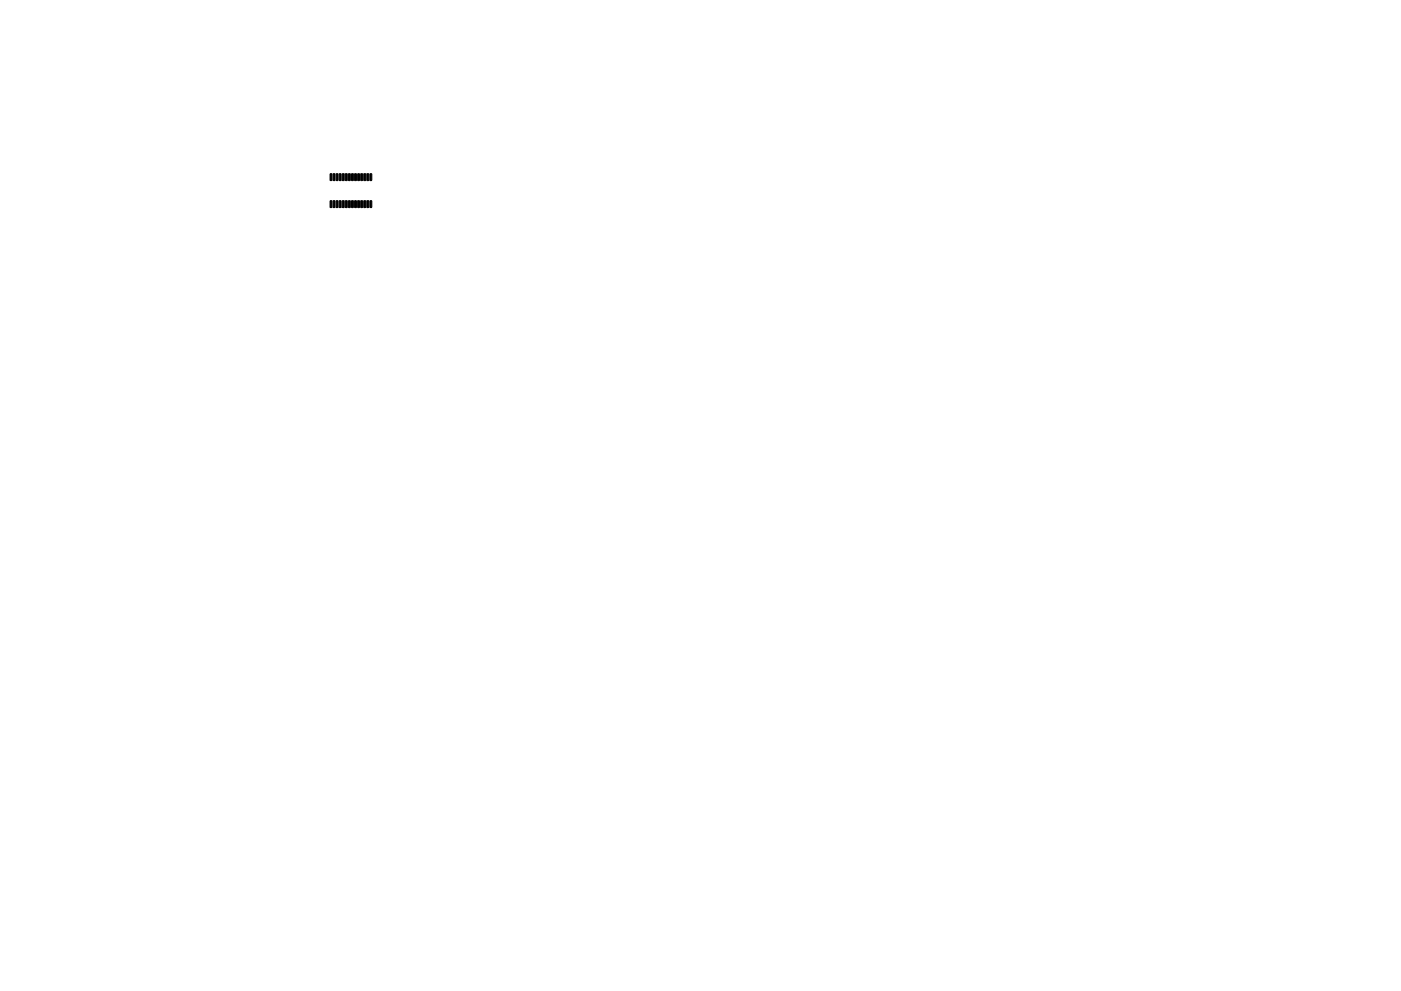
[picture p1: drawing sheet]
<svg xmlns="http://www.w3.org/2000/svg" width="297mm" height="210mm" viewBox="0 0 297 210" stroke-linecap="round" stroke-linejoin="round" font-family="sans-serif">
<g fill="#000" stroke="#000" stroke-width=".21">
<path d="M70 36.9h.4l-.1 1.4-.3-.1zM70.7 36.9h.3l-.1 1.4-.3-.1zM71.3 36.9h.4l-.1 1.4-.3-.1zM72 36.9h.3l-.1 1.4-.3-.1zM72.6 36.9h.4l-.1 1.4-.3-.1zM73.3 36.9h.3l-.1 1.4-.3-.1zM73.9 36.9h.4l-.1 1.4-.3-.1zM74.6 36.9h.3l-.1 1.4-.3-.1zM75.2 36.9h.4l-.1 1.4-.3-.1zM75.9 36.9h.3l-.1 1.4-.3-.1zM76.5 36.9h.4l-.1 1.4-.3-.1zM77.2 36.9h.3l-.1 1.4-.3-.1z"/>
<path d="M77.8 36.9h.4l-.1 1.4-.3-.1zM78.5 36.9h.3l-.1 1.4-.3-.1zM70 42.6l.4 .1-.1 1.3h-.3zM70.7 42.6l.3 .1-.1 1.3h-.3zM71.3 42.6l.4 .1-.1 1.3h-.3zM72 42.6l.3 .1-.1 1.3h-.3zM72.6 42.6l.4 .1-.1 1.3h-.3zM73.3 42.6l.3 .1-.1 1.3h-.3zM73.9 42.6l.4 .1-.1 1.3h-.3zM74.6 42.6l.3 .1-.1 1.3h-.3zM75.2 42.6l.4 .1-.1 1.3h-.3zM75.9 42.6l.3 .1-.1 1.3h-.3z"/>
<path d="M76.5 42.6l.4 .1-.1 1.3h-.3zM77.2 42.6l.3 .1-.1 1.3h-.3zM77.8 42.6l.4 .1-.1 1.3h-.3zM78.5 42.6l.3 .1-.1 1.3h-.3z"/>
</g>
</svg>
